# Generated by FakeRAM 2.0
VERSION 5.7 ;
BUSBITCHARS "[]" ;
PROPERTYDEFINITIONS
  MACRO width INTEGER ;
  MACRO depth INTEGER ;
  MACRO banks INTEGER ;
END PROPERTYDEFINITIONS
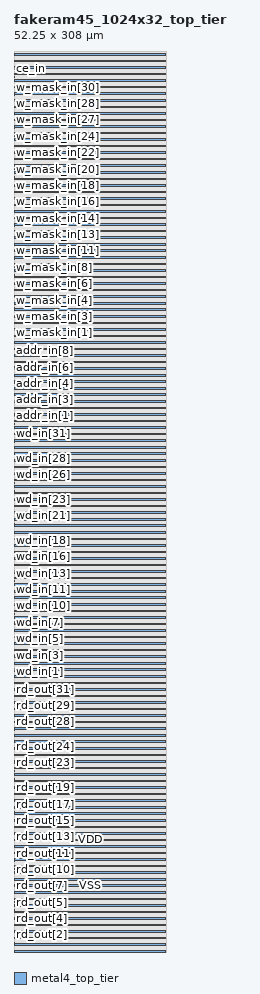
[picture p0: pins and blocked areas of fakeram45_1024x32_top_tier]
MACRO fakeram45_1024x32_top_tier
  PROPERTY width 32 ;
  PROPERTY depth 1024 ;
  PROPERTY banks 2 ;
  FOREIGN fakeram45_1024x32_top_tier 0 0 ;
  SYMMETRY X Y R90 ;
  SIZE 52.250 BY 308.000 ;
  CLASS BLOCK ;
  PIN rd_out[0]
    DIRECTION OUTPUT ;
    USE SIGNAL ;
    SHAPE ABUTMENT ;
    PORT
      LAYER metal4_top_tier ;
      RECT 0.000 0.280 0.140 0.420 ;
    END
  END rd_out[0]
  PIN rd_out[1]
    DIRECTION OUTPUT ;
    USE SIGNAL ;
    SHAPE ABUTMENT ;
    PORT
      LAYER metal4_top_tier ;
      RECT 0.000 3.080 0.140 3.220 ;
    END
  END rd_out[1]
  PIN rd_out[2]
    DIRECTION OUTPUT ;
    USE SIGNAL ;
    SHAPE ABUTMENT ;
    PORT
      LAYER metal4_top_tier ;
      RECT 0.000 5.880 0.140 6.020 ;
    END
  END rd_out[2]
  PIN rd_out[3]
    DIRECTION OUTPUT ;
    USE SIGNAL ;
    SHAPE ABUTMENT ;
    PORT
      LAYER metal4_top_tier ;
      RECT 0.000 8.680 0.140 8.820 ;
    END
  END rd_out[3]
  PIN rd_out[4]
    DIRECTION OUTPUT ;
    USE SIGNAL ;
    SHAPE ABUTMENT ;
    PORT
      LAYER metal4_top_tier ;
      RECT 0.000 11.480 0.140 11.620 ;
    END
  END rd_out[4]
  PIN rd_out[5]
    DIRECTION OUTPUT ;
    USE SIGNAL ;
    SHAPE ABUTMENT ;
    PORT
      LAYER metal4_top_tier ;
      RECT 0.000 14.280 0.140 14.420 ;
    END
  END rd_out[5]
  PIN rd_out[6]
    DIRECTION OUTPUT ;
    USE SIGNAL ;
    SHAPE ABUTMENT ;
    PORT
      LAYER metal4_top_tier ;
      RECT 0.000 17.080 0.140 17.220 ;
    END
  END rd_out[6]
  PIN rd_out[7]
    DIRECTION OUTPUT ;
    USE SIGNAL ;
    SHAPE ABUTMENT ;
    PORT
      LAYER metal4_top_tier ;
      RECT 0.000 19.880 0.140 20.020 ;
    END
  END rd_out[7]
  PIN rd_out[8]
    DIRECTION OUTPUT ;
    USE SIGNAL ;
    SHAPE ABUTMENT ;
    PORT
      LAYER metal4_top_tier ;
      RECT 0.000 22.680 0.140 22.820 ;
    END
  END rd_out[8]
  PIN rd_out[9]
    DIRECTION OUTPUT ;
    USE SIGNAL ;
    SHAPE ABUTMENT ;
    PORT
      LAYER metal4_top_tier ;
      RECT 0.000 25.480 0.140 25.620 ;
    END
  END rd_out[9]
  PIN rd_out[10]
    DIRECTION OUTPUT ;
    USE SIGNAL ;
    SHAPE ABUTMENT ;
    PORT
      LAYER metal4_top_tier ;
      RECT 0.000 28.280 0.140 28.420 ;
    END
  END rd_out[10]
  PIN rd_out[11]
    DIRECTION OUTPUT ;
    USE SIGNAL ;
    SHAPE ABUTMENT ;
    PORT
      LAYER metal4_top_tier ;
      RECT 0.000 31.080 0.140 31.220 ;
    END
  END rd_out[11]
  PIN rd_out[12]
    DIRECTION OUTPUT ;
    USE SIGNAL ;
    SHAPE ABUTMENT ;
    PORT
      LAYER metal4_top_tier ;
      RECT 0.000 33.880 0.140 34.020 ;
    END
  END rd_out[12]
  PIN rd_out[13]
    DIRECTION OUTPUT ;
    USE SIGNAL ;
    SHAPE ABUTMENT ;
    PORT
      LAYER metal4_top_tier ;
      RECT 0.000 36.680 0.140 36.820 ;
    END
  END rd_out[13]
  PIN rd_out[14]
    DIRECTION OUTPUT ;
    USE SIGNAL ;
    SHAPE ABUTMENT ;
    PORT
      LAYER metal4_top_tier ;
      RECT 0.000 39.480 0.140 39.620 ;
    END
  END rd_out[14]
  PIN rd_out[15]
    DIRECTION OUTPUT ;
    USE SIGNAL ;
    SHAPE ABUTMENT ;
    PORT
      LAYER metal4_top_tier ;
      RECT 0.000 42.280 0.140 42.420 ;
    END
  END rd_out[15]
  PIN rd_out[16]
    DIRECTION OUTPUT ;
    USE SIGNAL ;
    SHAPE ABUTMENT ;
    PORT
      LAYER metal4_top_tier ;
      RECT 0.000 45.080 0.140 45.220 ;
    END
  END rd_out[16]
  PIN rd_out[17]
    DIRECTION OUTPUT ;
    USE SIGNAL ;
    SHAPE ABUTMENT ;
    PORT
      LAYER metal4_top_tier ;
      RECT 0.000 47.880 0.140 48.020 ;
    END
  END rd_out[17]
  PIN rd_out[18]
    DIRECTION OUTPUT ;
    USE SIGNAL ;
    SHAPE ABUTMENT ;
    PORT
      LAYER metal4_top_tier ;
      RECT 0.000 50.680 0.140 50.820 ;
    END
  END rd_out[18]
  PIN rd_out[19]
    DIRECTION OUTPUT ;
    USE SIGNAL ;
    SHAPE ABUTMENT ;
    PORT
      LAYER metal4_top_tier ;
      RECT 0.000 53.480 0.140 53.620 ;
    END
  END rd_out[19]
  PIN rd_out[20]
    DIRECTION OUTPUT ;
    USE SIGNAL ;
    SHAPE ABUTMENT ;
    PORT
      LAYER metal4_top_tier ;
      RECT 0.000 56.280 0.140 56.420 ;
    END
  END rd_out[20]
  PIN rd_out[21]
    DIRECTION OUTPUT ;
    USE SIGNAL ;
    SHAPE ABUTMENT ;
    PORT
      LAYER metal4_top_tier ;
      RECT 0.000 59.080 0.140 59.220 ;
    END
  END rd_out[21]
  PIN rd_out[22]
    DIRECTION OUTPUT ;
    USE SIGNAL ;
    SHAPE ABUTMENT ;
    PORT
      LAYER metal4_top_tier ;
      RECT 0.000 61.880 0.140 62.020 ;
    END
  END rd_out[22]
  PIN rd_out[23]
    DIRECTION OUTPUT ;
    USE SIGNAL ;
    SHAPE ABUTMENT ;
    PORT
      LAYER metal4_top_tier ;
      RECT 0.000 64.680 0.140 64.820 ;
    END
  END rd_out[23]
  PIN rd_out[24]
    DIRECTION OUTPUT ;
    USE SIGNAL ;
    SHAPE ABUTMENT ;
    PORT
      LAYER metal4_top_tier ;
      RECT 0.000 67.480 0.140 67.620 ;
    END
  END rd_out[24]
  PIN rd_out[25]
    DIRECTION OUTPUT ;
    USE SIGNAL ;
    SHAPE ABUTMENT ;
    PORT
      LAYER metal4_top_tier ;
      RECT 0.000 70.280 0.140 70.420 ;
    END
  END rd_out[25]
  PIN rd_out[26]
    DIRECTION OUTPUT ;
    USE SIGNAL ;
    SHAPE ABUTMENT ;
    PORT
      LAYER metal4_top_tier ;
      RECT 0.000 73.080 0.140 73.220 ;
    END
  END rd_out[26]
  PIN rd_out[27]
    DIRECTION OUTPUT ;
    USE SIGNAL ;
    SHAPE ABUTMENT ;
    PORT
      LAYER metal4_top_tier ;
      RECT 0.000 75.880 0.140 76.020 ;
    END
  END rd_out[27]
  PIN rd_out[28]
    DIRECTION OUTPUT ;
    USE SIGNAL ;
    SHAPE ABUTMENT ;
    PORT
      LAYER metal4_top_tier ;
      RECT 0.000 78.680 0.140 78.820 ;
    END
  END rd_out[28]
  PIN rd_out[29]
    DIRECTION OUTPUT ;
    USE SIGNAL ;
    SHAPE ABUTMENT ;
    PORT
      LAYER metal4_top_tier ;
      RECT 0.000 81.480 0.140 81.620 ;
    END
  END rd_out[29]
  PIN rd_out[30]
    DIRECTION OUTPUT ;
    USE SIGNAL ;
    SHAPE ABUTMENT ;
    PORT
      LAYER metal4_top_tier ;
      RECT 0.000 84.280 0.140 84.420 ;
    END
  END rd_out[30]
  PIN rd_out[31]
    DIRECTION OUTPUT ;
    USE SIGNAL ;
    SHAPE ABUTMENT ;
    PORT
      LAYER metal4_top_tier ;
      RECT 0.000 87.080 0.140 87.220 ;
    END
  END rd_out[31]
  PIN wd_in[0]
    DIRECTION INPUT ;
    USE SIGNAL ;
    SHAPE ABUTMENT ;
    PORT
      LAYER metal4_top_tier ;
      RECT 0.000 90.440 0.140 90.580 ;
    END
  END wd_in[0]
  PIN wd_in[1]
    DIRECTION INPUT ;
    USE SIGNAL ;
    SHAPE ABUTMENT ;
    PORT
      LAYER metal4_top_tier ;
      RECT 0.000 93.240 0.140 93.380 ;
    END
  END wd_in[1]
  PIN wd_in[2]
    DIRECTION INPUT ;
    USE SIGNAL ;
    SHAPE ABUTMENT ;
    PORT
      LAYER metal4_top_tier ;
      RECT 0.000 96.040 0.140 96.180 ;
    END
  END wd_in[2]
  PIN wd_in[3]
    DIRECTION INPUT ;
    USE SIGNAL ;
    SHAPE ABUTMENT ;
    PORT
      LAYER metal4_top_tier ;
      RECT 0.000 98.840 0.140 98.980 ;
    END
  END wd_in[3]
  PIN wd_in[4]
    DIRECTION INPUT ;
    USE SIGNAL ;
    SHAPE ABUTMENT ;
    PORT
      LAYER metal4_top_tier ;
      RECT 0.000 101.640 0.140 101.780 ;
    END
  END wd_in[4]
  PIN wd_in[5]
    DIRECTION INPUT ;
    USE SIGNAL ;
    SHAPE ABUTMENT ;
    PORT
      LAYER metal4_top_tier ;
      RECT 0.000 104.440 0.140 104.580 ;
    END
  END wd_in[5]
  PIN wd_in[6]
    DIRECTION INPUT ;
    USE SIGNAL ;
    SHAPE ABUTMENT ;
    PORT
      LAYER metal4_top_tier ;
      RECT 0.000 107.240 0.140 107.380 ;
    END
  END wd_in[6]
  PIN wd_in[7]
    DIRECTION INPUT ;
    USE SIGNAL ;
    SHAPE ABUTMENT ;
    PORT
      LAYER metal4_top_tier ;
      RECT 0.000 110.040 0.140 110.180 ;
    END
  END wd_in[7]
  PIN wd_in[8]
    DIRECTION INPUT ;
    USE SIGNAL ;
    SHAPE ABUTMENT ;
    PORT
      LAYER metal4_top_tier ;
      RECT 0.000 112.840 0.140 112.980 ;
    END
  END wd_in[8]
  PIN wd_in[9]
    DIRECTION INPUT ;
    USE SIGNAL ;
    SHAPE ABUTMENT ;
    PORT
      LAYER metal4_top_tier ;
      RECT 0.000 115.640 0.140 115.780 ;
    END
  END wd_in[9]
  PIN wd_in[10]
    DIRECTION INPUT ;
    USE SIGNAL ;
    SHAPE ABUTMENT ;
    PORT
      LAYER metal4_top_tier ;
      RECT 0.000 118.440 0.140 118.580 ;
    END
  END wd_in[10]
  PIN wd_in[11]
    DIRECTION INPUT ;
    USE SIGNAL ;
    SHAPE ABUTMENT ;
    PORT
      LAYER metal4_top_tier ;
      RECT 0.000 121.240 0.140 121.380 ;
    END
  END wd_in[11]
  PIN wd_in[12]
    DIRECTION INPUT ;
    USE SIGNAL ;
    SHAPE ABUTMENT ;
    PORT
      LAYER metal4_top_tier ;
      RECT 0.000 124.040 0.140 124.180 ;
    END
  END wd_in[12]
  PIN wd_in[13]
    DIRECTION INPUT ;
    USE SIGNAL ;
    SHAPE ABUTMENT ;
    PORT
      LAYER metal4_top_tier ;
      RECT 0.000 126.840 0.140 126.980 ;
    END
  END wd_in[13]
  PIN wd_in[14]
    DIRECTION INPUT ;
    USE SIGNAL ;
    SHAPE ABUTMENT ;
    PORT
      LAYER metal4_top_tier ;
      RECT 0.000 129.640 0.140 129.780 ;
    END
  END wd_in[14]
  PIN wd_in[15]
    DIRECTION INPUT ;
    USE SIGNAL ;
    SHAPE ABUTMENT ;
    PORT
      LAYER metal4_top_tier ;
      RECT 0.000 132.440 0.140 132.580 ;
    END
  END wd_in[15]
  PIN wd_in[16]
    DIRECTION INPUT ;
    USE SIGNAL ;
    SHAPE ABUTMENT ;
    PORT
      LAYER metal4_top_tier ;
      RECT 0.000 135.240 0.140 135.380 ;
    END
  END wd_in[16]
  PIN wd_in[17]
    DIRECTION INPUT ;
    USE SIGNAL ;
    SHAPE ABUTMENT ;
    PORT
      LAYER metal4_top_tier ;
      RECT 0.000 138.040 0.140 138.180 ;
    END
  END wd_in[17]
  PIN wd_in[18]
    DIRECTION INPUT ;
    USE SIGNAL ;
    SHAPE ABUTMENT ;
    PORT
      LAYER metal4_top_tier ;
      RECT 0.000 140.840 0.140 140.980 ;
    END
  END wd_in[18]
  PIN wd_in[19]
    DIRECTION INPUT ;
    USE SIGNAL ;
    SHAPE ABUTMENT ;
    PORT
      LAYER metal4_top_tier ;
      RECT 0.000 143.640 0.140 143.780 ;
    END
  END wd_in[19]
  PIN wd_in[20]
    DIRECTION INPUT ;
    USE SIGNAL ;
    SHAPE ABUTMENT ;
    PORT
      LAYER metal4_top_tier ;
      RECT 0.000 146.440 0.140 146.580 ;
    END
  END wd_in[20]
  PIN wd_in[21]
    DIRECTION INPUT ;
    USE SIGNAL ;
    SHAPE ABUTMENT ;
    PORT
      LAYER metal4_top_tier ;
      RECT 0.000 149.240 0.140 149.380 ;
    END
  END wd_in[21]
  PIN wd_in[22]
    DIRECTION INPUT ;
    USE SIGNAL ;
    SHAPE ABUTMENT ;
    PORT
      LAYER metal4_top_tier ;
      RECT 0.000 152.040 0.140 152.180 ;
    END
  END wd_in[22]
  PIN wd_in[23]
    DIRECTION INPUT ;
    USE SIGNAL ;
    SHAPE ABUTMENT ;
    PORT
      LAYER metal4_top_tier ;
      RECT 0.000 154.840 0.140 154.980 ;
    END
  END wd_in[23]
  PIN wd_in[24]
    DIRECTION INPUT ;
    USE SIGNAL ;
    SHAPE ABUTMENT ;
    PORT
      LAYER metal4_top_tier ;
      RECT 0.000 157.640 0.140 157.780 ;
    END
  END wd_in[24]
  PIN wd_in[25]
    DIRECTION INPUT ;
    USE SIGNAL ;
    SHAPE ABUTMENT ;
    PORT
      LAYER metal4_top_tier ;
      RECT 0.000 160.440 0.140 160.580 ;
    END
  END wd_in[25]
  PIN wd_in[26]
    DIRECTION INPUT ;
    USE SIGNAL ;
    SHAPE ABUTMENT ;
    PORT
      LAYER metal4_top_tier ;
      RECT 0.000 163.240 0.140 163.380 ;
    END
  END wd_in[26]
  PIN wd_in[27]
    DIRECTION INPUT ;
    USE SIGNAL ;
    SHAPE ABUTMENT ;
    PORT
      LAYER metal4_top_tier ;
      RECT 0.000 166.040 0.140 166.180 ;
    END
  END wd_in[27]
  PIN wd_in[28]
    DIRECTION INPUT ;
    USE SIGNAL ;
    SHAPE ABUTMENT ;
    PORT
      LAYER metal4_top_tier ;
      RECT 0.000 168.840 0.140 168.980 ;
    END
  END wd_in[28]
  PIN wd_in[29]
    DIRECTION INPUT ;
    USE SIGNAL ;
    SHAPE ABUTMENT ;
    PORT
      LAYER metal4_top_tier ;
      RECT 0.000 171.640 0.140 171.780 ;
    END
  END wd_in[29]
  PIN wd_in[30]
    DIRECTION INPUT ;
    USE SIGNAL ;
    SHAPE ABUTMENT ;
    PORT
      LAYER metal4_top_tier ;
      RECT 0.000 174.440 0.140 174.580 ;
    END
  END wd_in[30]
  PIN wd_in[31]
    DIRECTION INPUT ;
    USE SIGNAL ;
    SHAPE ABUTMENT ;
    PORT
      LAYER metal4_top_tier ;
      RECT 0.000 177.240 0.140 177.380 ;
    END
  END wd_in[31]
  PIN addr_in[0]
    DIRECTION INPUT ;
    USE SIGNAL ;
    SHAPE ABUTMENT ;
    PORT
      LAYER metal4_top_tier ;
      RECT 0.000 180.600 0.140 180.740 ;
    END
  END addr_in[0]
  PIN addr_in[1]
    DIRECTION INPUT ;
    USE SIGNAL ;
    SHAPE ABUTMENT ;
    PORT
      LAYER metal4_top_tier ;
      RECT 0.000 183.400 0.140 183.540 ;
    END
  END addr_in[1]
  PIN addr_in[2]
    DIRECTION INPUT ;
    USE SIGNAL ;
    SHAPE ABUTMENT ;
    PORT
      LAYER metal4_top_tier ;
      RECT 0.000 186.200 0.140 186.340 ;
    END
  END addr_in[2]
  PIN addr_in[3]
    DIRECTION INPUT ;
    USE SIGNAL ;
    SHAPE ABUTMENT ;
    PORT
      LAYER metal4_top_tier ;
      RECT 0.000 189.000 0.140 189.140 ;
    END
  END addr_in[3]
  PIN addr_in[4]
    DIRECTION INPUT ;
    USE SIGNAL ;
    SHAPE ABUTMENT ;
    PORT
      LAYER metal4_top_tier ;
      RECT 0.000 191.800 0.140 191.940 ;
    END
  END addr_in[4]
  PIN addr_in[5]
    DIRECTION INPUT ;
    USE SIGNAL ;
    SHAPE ABUTMENT ;
    PORT
      LAYER metal4_top_tier ;
      RECT 0.000 194.600 0.140 194.740 ;
    END
  END addr_in[5]
  PIN addr_in[6]
    DIRECTION INPUT ;
    USE SIGNAL ;
    SHAPE ABUTMENT ;
    PORT
      LAYER metal4_top_tier ;
      RECT 0.000 197.400 0.140 197.540 ;
    END
  END addr_in[6]
  PIN addr_in[7]
    DIRECTION INPUT ;
    USE SIGNAL ;
    SHAPE ABUTMENT ;
    PORT
      LAYER metal4_top_tier ;
      RECT 0.000 200.200 0.140 200.340 ;
    END
  END addr_in[7]
  PIN addr_in[8]
    DIRECTION INPUT ;
    USE SIGNAL ;
    SHAPE ABUTMENT ;
    PORT
      LAYER metal4_top_tier ;
      RECT 0.000 203.000 0.140 203.140 ;
    END
  END addr_in[8]
  PIN addr_in[9]
    DIRECTION INPUT ;
    USE SIGNAL ;
    SHAPE ABUTMENT ;
    PORT
      LAYER metal4_top_tier ;
      RECT 0.000 205.800 0.140 205.940 ;
    END
  END addr_in[9]
  PIN w_mask_in[0]
    DIRECTION OUTPUT ;
    USE SIGNAL ;
    SHAPE ABUTMENT ;
    PORT
      LAYER metal4_top_tier ;
      RECT 0.000 209.160 0.140 209.300 ;
    END
  END w_mask_in[0]
  PIN w_mask_in[1]
    DIRECTION OUTPUT ;
    USE SIGNAL ;
    SHAPE ABUTMENT ;
    PORT
      LAYER metal4_top_tier ;
      RECT 0.000 211.960 0.140 212.100 ;
    END
  END w_mask_in[1]
  PIN w_mask_in[2]
    DIRECTION OUTPUT ;
    USE SIGNAL ;
    SHAPE ABUTMENT ;
    PORT
      LAYER metal4_top_tier ;
      RECT 0.000 214.760 0.140 214.900 ;
    END
  END w_mask_in[2]
  PIN w_mask_in[3]
    DIRECTION OUTPUT ;
    USE SIGNAL ;
    SHAPE ABUTMENT ;
    PORT
      LAYER metal4_top_tier ;
      RECT 0.000 217.560 0.140 217.700 ;
    END
  END w_mask_in[3]
  PIN w_mask_in[4]
    DIRECTION OUTPUT ;
    USE SIGNAL ;
    SHAPE ABUTMENT ;
    PORT
      LAYER metal4_top_tier ;
      RECT 0.000 220.360 0.140 220.500 ;
    END
  END w_mask_in[4]
  PIN w_mask_in[5]
    DIRECTION OUTPUT ;
    USE SIGNAL ;
    SHAPE ABUTMENT ;
    PORT
      LAYER metal4_top_tier ;
      RECT 0.000 223.160 0.140 223.300 ;
    END
  END w_mask_in[5]
  PIN w_mask_in[6]
    DIRECTION OUTPUT ;
    USE SIGNAL ;
    SHAPE ABUTMENT ;
    PORT
      LAYER metal4_top_tier ;
      RECT 0.000 225.960 0.140 226.100 ;
    END
  END w_mask_in[6]
  PIN w_mask_in[7]
    DIRECTION OUTPUT ;
    USE SIGNAL ;
    SHAPE ABUTMENT ;
    PORT
      LAYER metal4_top_tier ;
      RECT 0.000 228.760 0.140 228.900 ;
    END
  END w_mask_in[7]
  PIN w_mask_in[8]
    DIRECTION OUTPUT ;
    USE SIGNAL ;
    SHAPE ABUTMENT ;
    PORT
      LAYER metal4_top_tier ;
      RECT 0.000 231.560 0.140 231.700 ;
    END
  END w_mask_in[8]
  PIN w_mask_in[9]
    DIRECTION OUTPUT ;
    USE SIGNAL ;
    SHAPE ABUTMENT ;
    PORT
      LAYER metal4_top_tier ;
      RECT 0.000 234.360 0.140 234.500 ;
    END
  END w_mask_in[9]
  PIN w_mask_in[10]
    DIRECTION OUTPUT ;
    USE SIGNAL ;
    SHAPE ABUTMENT ;
    PORT
      LAYER metal4_top_tier ;
      RECT 0.000 237.160 0.140 237.300 ;
    END
  END w_mask_in[10]
  PIN w_mask_in[11]
    DIRECTION OUTPUT ;
    USE SIGNAL ;
    SHAPE ABUTMENT ;
    PORT
      LAYER metal4_top_tier ;
      RECT 0.000 239.960 0.140 240.100 ;
    END
  END w_mask_in[11]
  PIN w_mask_in[12]
    DIRECTION OUTPUT ;
    USE SIGNAL ;
    SHAPE ABUTMENT ;
    PORT
      LAYER metal4_top_tier ;
      RECT 0.000 242.760 0.140 242.900 ;
    END
  END w_mask_in[12]
  PIN w_mask_in[13]
    DIRECTION OUTPUT ;
    USE SIGNAL ;
    SHAPE ABUTMENT ;
    PORT
      LAYER metal4_top_tier ;
      RECT 0.000 245.560 0.140 245.700 ;
    END
  END w_mask_in[13]
  PIN w_mask_in[14]
    DIRECTION OUTPUT ;
    USE SIGNAL ;
    SHAPE ABUTMENT ;
    PORT
      LAYER metal4_top_tier ;
      RECT 0.000 248.360 0.140 248.500 ;
    END
  END w_mask_in[14]
  PIN w_mask_in[15]
    DIRECTION OUTPUT ;
    USE SIGNAL ;
    SHAPE ABUTMENT ;
    PORT
      LAYER metal4_top_tier ;
      RECT 0.000 251.160 0.140 251.300 ;
    END
  END w_mask_in[15]
  PIN w_mask_in[16]
    DIRECTION OUTPUT ;
    USE SIGNAL ;
    SHAPE ABUTMENT ;
    PORT
      LAYER metal4_top_tier ;
      RECT 0.000 253.960 0.140 254.100 ;
    END
  END w_mask_in[16]
  PIN w_mask_in[17]
    DIRECTION OUTPUT ;
    USE SIGNAL ;
    SHAPE ABUTMENT ;
    PORT
      LAYER metal4_top_tier ;
      RECT 0.000 256.760 0.140 256.900 ;
    END
  END w_mask_in[17]
  PIN w_mask_in[18]
    DIRECTION OUTPUT ;
    USE SIGNAL ;
    SHAPE ABUTMENT ;
    PORT
      LAYER metal4_top_tier ;
      RECT 0.000 259.560 0.140 259.700 ;
    END
  END w_mask_in[18]
  PIN w_mask_in[19]
    DIRECTION OUTPUT ;
    USE SIGNAL ;
    SHAPE ABUTMENT ;
    PORT
      LAYER metal4_top_tier ;
      RECT 0.000 262.360 0.140 262.500 ;
    END
  END w_mask_in[19]
  PIN w_mask_in[20]
    DIRECTION OUTPUT ;
    USE SIGNAL ;
    SHAPE ABUTMENT ;
    PORT
      LAYER metal4_top_tier ;
      RECT 0.000 265.160 0.140 265.300 ;
    END
  END w_mask_in[20]
  PIN w_mask_in[21]
    DIRECTION OUTPUT ;
    USE SIGNAL ;
    SHAPE ABUTMENT ;
    PORT
      LAYER metal4_top_tier ;
      RECT 0.000 267.960 0.140 268.100 ;
    END
  END w_mask_in[21]
  PIN w_mask_in[22]
    DIRECTION OUTPUT ;
    USE SIGNAL ;
    SHAPE ABUTMENT ;
    PORT
      LAYER metal4_top_tier ;
      RECT 0.000 270.760 0.140 270.900 ;
    END
  END w_mask_in[22]
  PIN w_mask_in[23]
    DIRECTION OUTPUT ;
    USE SIGNAL ;
    SHAPE ABUTMENT ;
    PORT
      LAYER metal4_top_tier ;
      RECT 0.000 273.560 0.140 273.700 ;
    END
  END w_mask_in[23]
  PIN w_mask_in[24]
    DIRECTION OUTPUT ;
    USE SIGNAL ;
    SHAPE ABUTMENT ;
    PORT
      LAYER metal4_top_tier ;
      RECT 0.000 276.360 0.140 276.500 ;
    END
  END w_mask_in[24]
  PIN w_mask_in[25]
    DIRECTION OUTPUT ;
    USE SIGNAL ;
    SHAPE ABUTMENT ;
    PORT
      LAYER metal4_top_tier ;
      RECT 0.000 279.160 0.140 279.300 ;
    END
  END w_mask_in[25]
  PIN w_mask_in[26]
    DIRECTION OUTPUT ;
    USE SIGNAL ;
    SHAPE ABUTMENT ;
    PORT
      LAYER metal4_top_tier ;
      RECT 0.000 281.960 0.140 282.100 ;
    END
  END w_mask_in[26]
  PIN w_mask_in[27]
    DIRECTION OUTPUT ;
    USE SIGNAL ;
    SHAPE ABUTMENT ;
    PORT
      LAYER metal4_top_tier ;
      RECT 0.000 284.760 0.140 284.900 ;
    END
  END w_mask_in[27]
  PIN w_mask_in[28]
    DIRECTION OUTPUT ;
    USE SIGNAL ;
    SHAPE ABUTMENT ;
    PORT
      LAYER metal4_top_tier ;
      RECT 0.000 287.560 0.140 287.700 ;
    END
  END w_mask_in[28]
  PIN w_mask_in[29]
    DIRECTION OUTPUT ;
    USE SIGNAL ;
    SHAPE ABUTMENT ;
    PORT
      LAYER metal4_top_tier ;
      RECT 0.000 290.360 0.140 290.500 ;
    END
  END w_mask_in[29]
  PIN w_mask_in[30]
    DIRECTION OUTPUT ;
    USE SIGNAL ;
    SHAPE ABUTMENT ;
    PORT
      LAYER metal4_top_tier ;
      RECT 0.000 293.160 0.140 293.300 ;
    END
  END w_mask_in[30]
  PIN w_mask_in[31]
    DIRECTION OUTPUT ;
    USE SIGNAL ;
    SHAPE ABUTMENT ;
    PORT
      LAYER metal4_top_tier ;
      RECT 0.000 295.960 0.140 296.100 ;
    END
  END w_mask_in[31]
  PIN we_in
    DIRECTION INPUT ;
    USE SIGNAL ;
    SHAPE ABUTMENT ;
    PORT
      LAYER metal4_top_tier ;
      RECT 0.000 299.320 0.140 299.460 ;
    END
  END we_in
  PIN ce_in
    DIRECTION INPUT ;
    USE SIGNAL ;
    SHAPE ABUTMENT ;
    PORT
      LAYER metal4_top_tier ;
      RECT 0.000 302.120 0.140 302.260 ;
    END
  END ce_in
  PIN clk
    DIRECTION INPUT ;
    USE SIGNAL ;
    SHAPE ABUTMENT ;
    PORT
      LAYER metal4_top_tier ;
      RECT 0.000 304.920 0.140 305.060 ;
    END
  END clk
  PIN VSS
    DIRECTION INOUT ;
    USE GROUND ;
    PORT
      LAYER metal4_top_tier ;
      RECT 0.280 0.000 51.970 0.560 ;
      RECT 0.280 4.480 51.970 5.040 ;
      RECT 0.280 8.960 51.970 9.520 ;
      RECT 0.280 13.440 51.970 14.000 ;
      RECT 0.280 17.920 51.970 18.480 ;
      RECT 0.280 22.400 51.970 22.960 ;
      RECT 0.280 26.880 51.970 27.440 ;
      RECT 0.280 31.360 51.970 31.920 ;
      RECT 0.280 35.840 51.970 36.400 ;
      RECT 0.280 40.320 51.970 40.880 ;
      RECT 0.280 44.800 51.970 45.360 ;
      RECT 0.280 49.280 51.970 49.840 ;
      RECT 0.280 53.760 51.970 54.320 ;
      RECT 0.280 58.240 51.970 58.800 ;
      RECT 0.280 62.720 51.970 63.280 ;
      RECT 0.280 67.200 51.970 67.760 ;
      RECT 0.280 71.680 51.970 72.240 ;
      RECT 0.280 76.160 51.970 76.720 ;
      RECT 0.280 80.640 51.970 81.200 ;
      RECT 0.280 85.120 51.970 85.680 ;
      RECT 0.280 89.600 51.970 90.160 ;
      RECT 0.280 94.080 51.970 94.640 ;
      RECT 0.280 98.560 51.970 99.120 ;
      RECT 0.280 103.040 51.970 103.600 ;
      RECT 0.280 107.520 51.970 108.080 ;
      RECT 0.280 112.000 51.970 112.560 ;
      RECT 0.280 116.480 51.970 117.040 ;
      RECT 0.280 120.960 51.970 121.520 ;
      RECT 0.280 125.440 51.970 126.000 ;
      RECT 0.280 129.920 51.970 130.480 ;
      RECT 0.280 134.400 51.970 134.960 ;
      RECT 0.280 138.880 51.970 139.440 ;
      RECT 0.280 143.360 51.970 143.920 ;
      RECT 0.280 147.840 51.970 148.400 ;
      RECT 0.280 152.320 51.970 152.880 ;
      RECT 0.280 156.800 51.970 157.360 ;
      RECT 0.280 161.280 51.970 161.840 ;
      RECT 0.280 165.760 51.970 166.320 ;
      RECT 0.280 170.240 51.970 170.800 ;
      RECT 0.280 174.720 51.970 175.280 ;
      RECT 0.280 179.200 51.970 179.760 ;
      RECT 0.280 183.680 51.970 184.240 ;
      RECT 0.280 188.160 51.970 188.720 ;
      RECT 0.280 192.640 51.970 193.200 ;
      RECT 0.280 197.120 51.970 197.680 ;
      RECT 0.280 201.600 51.970 202.160 ;
      RECT 0.280 206.080 51.970 206.640 ;
      RECT 0.280 210.560 51.970 211.120 ;
      RECT 0.280 215.040 51.970 215.600 ;
      RECT 0.280 219.520 51.970 220.080 ;
      RECT 0.280 224.000 51.970 224.560 ;
      RECT 0.280 228.480 51.970 229.040 ;
      RECT 0.280 232.960 51.970 233.520 ;
      RECT 0.280 237.440 51.970 238.000 ;
      RECT 0.280 241.920 51.970 242.480 ;
      RECT 0.280 246.400 51.970 246.960 ;
      RECT 0.280 250.880 51.970 251.440 ;
      RECT 0.280 255.360 51.970 255.920 ;
      RECT 0.280 259.840 51.970 260.400 ;
      RECT 0.280 264.320 51.970 264.880 ;
      RECT 0.280 268.800 51.970 269.360 ;
      RECT 0.280 273.280 51.970 273.840 ;
      RECT 0.280 277.760 51.970 278.320 ;
      RECT 0.280 282.240 51.970 282.800 ;
      RECT 0.280 286.720 51.970 287.280 ;
      RECT 0.280 291.200 51.970 291.760 ;
      RECT 0.280 295.680 51.970 296.240 ;
      RECT 0.280 300.160 51.970 300.720 ;
      RECT 0.280 304.640 51.970 305.200 ;
    END
  END VSS
  PIN VDD
    DIRECTION INOUT ;
    USE POWER ;
    PORT
      LAYER metal4_top_tier ;
      RECT 0.280 2.240 51.970 2.800 ;
      RECT 0.280 6.720 51.970 7.280 ;
      RECT 0.280 11.200 51.970 11.760 ;
      RECT 0.280 15.680 51.970 16.240 ;
      RECT 0.280 20.160 51.970 20.720 ;
      RECT 0.280 24.640 51.970 25.200 ;
      RECT 0.280 29.120 51.970 29.680 ;
      RECT 0.280 33.600 51.970 34.160 ;
      RECT 0.280 38.080 51.970 38.640 ;
      RECT 0.280 42.560 51.970 43.120 ;
      RECT 0.280 47.040 51.970 47.600 ;
      RECT 0.280 51.520 51.970 52.080 ;
      RECT 0.280 56.000 51.970 56.560 ;
      RECT 0.280 60.480 51.970 61.040 ;
      RECT 0.280 64.960 51.970 65.520 ;
      RECT 0.280 69.440 51.970 70.000 ;
      RECT 0.280 73.920 51.970 74.480 ;
      RECT 0.280 78.400 51.970 78.960 ;
      RECT 0.280 82.880 51.970 83.440 ;
      RECT 0.280 87.360 51.970 87.920 ;
      RECT 0.280 91.840 51.970 92.400 ;
      RECT 0.280 96.320 51.970 96.880 ;
      RECT 0.280 100.800 51.970 101.360 ;
      RECT 0.280 105.280 51.970 105.840 ;
      RECT 0.280 109.760 51.970 110.320 ;
      RECT 0.280 114.240 51.970 114.800 ;
      RECT 0.280 118.720 51.970 119.280 ;
      RECT 0.280 123.200 51.970 123.760 ;
      RECT 0.280 127.680 51.970 128.240 ;
      RECT 0.280 132.160 51.970 132.720 ;
      RECT 0.280 136.640 51.970 137.200 ;
      RECT 0.280 141.120 51.970 141.680 ;
      RECT 0.280 145.600 51.970 146.160 ;
      RECT 0.280 150.080 51.970 150.640 ;
      RECT 0.280 154.560 51.970 155.120 ;
      RECT 0.280 159.040 51.970 159.600 ;
      RECT 0.280 163.520 51.970 164.080 ;
      RECT 0.280 168.000 51.970 168.560 ;
      RECT 0.280 172.480 51.970 173.040 ;
      RECT 0.280 176.960 51.970 177.520 ;
      RECT 0.280 181.440 51.970 182.000 ;
      RECT 0.280 185.920 51.970 186.480 ;
      RECT 0.280 190.400 51.970 190.960 ;
      RECT 0.280 194.880 51.970 195.440 ;
      RECT 0.280 199.360 51.970 199.920 ;
      RECT 0.280 203.840 51.970 204.400 ;
      RECT 0.280 208.320 51.970 208.880 ;
      RECT 0.280 212.800 51.970 213.360 ;
      RECT 0.280 217.280 51.970 217.840 ;
      RECT 0.280 221.760 51.970 222.320 ;
      RECT 0.280 226.240 51.970 226.800 ;
      RECT 0.280 230.720 51.970 231.280 ;
      RECT 0.280 235.200 51.970 235.760 ;
      RECT 0.280 239.680 51.970 240.240 ;
      RECT 0.280 244.160 51.970 244.720 ;
      RECT 0.280 248.640 51.970 249.200 ;
      RECT 0.280 253.120 51.970 253.680 ;
      RECT 0.280 257.600 51.970 258.160 ;
      RECT 0.280 262.080 51.970 262.640 ;
      RECT 0.280 266.560 51.970 267.120 ;
      RECT 0.280 271.040 51.970 271.600 ;
      RECT 0.280 275.520 51.970 276.080 ;
      RECT 0.280 280.000 51.970 280.560 ;
      RECT 0.280 284.480 51.970 285.040 ;
      RECT 0.280 288.960 51.970 289.520 ;
      RECT 0.280 293.440 51.970 294.000 ;
      RECT 0.280 297.920 51.970 298.480 ;
      RECT 0.280 302.400 51.970 302.960 ;
      RECT 0.280 306.880 51.970 307.440 ;
    END
  END VDD
  OBS
    LAYER metal1_top_tier ;
    RECT 0 0 52.250 308.000 ;
    LAYER metal2_top_tier ;
    RECT 0 0 52.250 308.000 ;
    LAYER metal3_top_tier ;
    RECT 0 0 52.250 308.000 ;
    LAYER metal4_top_tier ;
    RECT 0 0 52.250 308.000 ;
  END
END fakeram45_1024x32_top_tier

END LIBRARY
